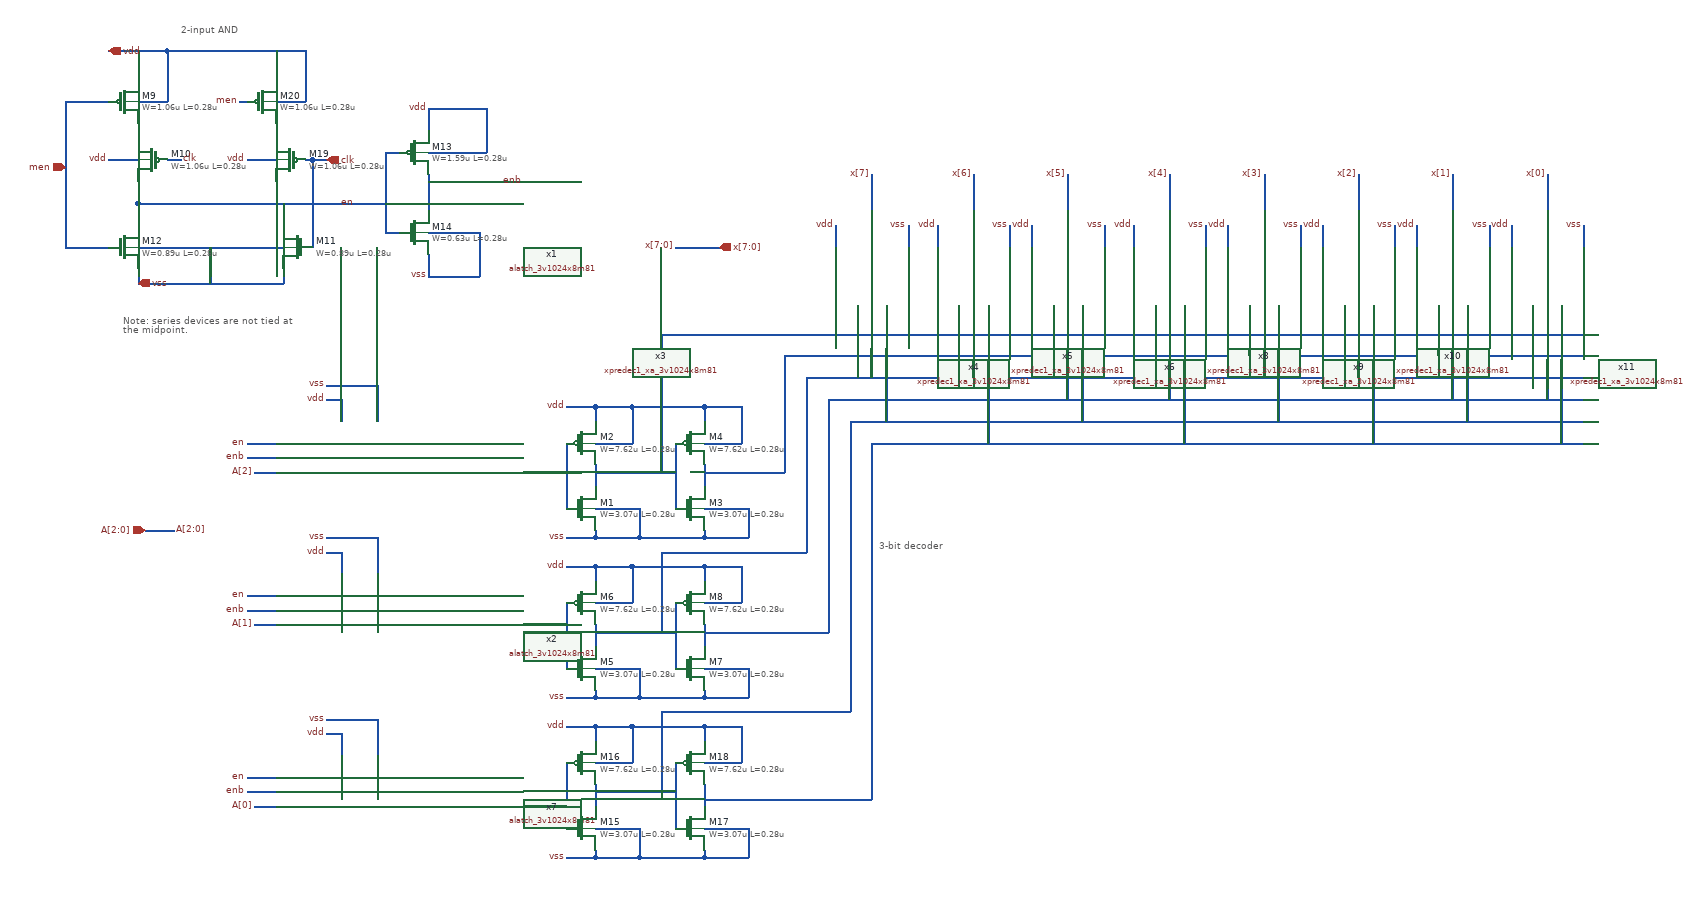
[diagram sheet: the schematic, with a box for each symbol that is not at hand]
v {xschem version=3.4.6 file_version=1.2}
G {}
K {}
V {}
S {}
E {}
T {2-input AND} -90 -410 0 0 0.4 0.4 {}
T {3-bit decoder} 870 300 0 0 0.4 0.4 {}
T {Note: series devices are not tied at
the midpoint.} -170 -10 0 0 0.3 0.3 {}
N 10 210 40 210 {lab=A[2]}
N 10 420 40 420 {lab=A[1]}
N -140 290 -100 290 {lab=A[2:0]}
N 860 -200 860 -150 {lab=x[7]}
N 1000 -200 1000 -150 {lab=x[6]}
N 1130 -200 1130 -150 {lab=x[5]}
N 1270 -200 1270 -150 {lab=x[4]}
N 440 170 440 260 {lab=#net1}
N 480 120 480 140 {lab=vdd}
N 480 120 530 120 {lab=vdd}
N 530 120 530 170 {lab=vdd}
N 480 170 530 170 {lab=vdd}
N 480 260 540 260 {lab=vss}
N 540 260 540 300 {lab=vss}
N 480 300 540 300 {lab=vss}
N 480 290 480 300 {lab=vss}
N 480 200 480 230 {lab=#net2}
N 480 210 590 210 {lab=#net2}
N 590 170 590 260 {lab=#net2}
N 630 120 630 140 {lab=vdd}
N 630 120 680 120 {lab=vdd}
N 680 120 680 170 {lab=vdd}
N 630 170 680 170 {lab=vdd}
N 630 260 690 260 {lab=vss}
N 690 260 690 300 {lab=vss}
N 630 300 690 300 {lab=vss}
N 630 290 630 300 {lab=vss}
N 630 200 630 230 {lab=#net3}
N 630 210 740 210 {lab=#net3}
N 250 210 440 210 {lab=#net1}
N 530 120 630 120 {lab=vdd}
N 540 300 630 300 {lab=vss}
N 440 300 480 300 {lab=vss}
N 440 120 480 120 {lab=vdd}
N 440 390 440 480 {lab=#net4}
N 480 340 480 360 {lab=vdd}
N 480 340 530 340 {lab=vdd}
N 530 340 530 390 {lab=vdd}
N 480 390 530 390 {lab=vdd}
N 480 480 540 480 {lab=vss}
N 540 480 540 520 {lab=vss}
N 480 520 540 520 {lab=vss}
N 480 510 480 520 {lab=vss}
N 480 420 480 450 {lab=#net5}
N 480 430 590 430 {lab=#net5}
N 590 390 590 480 {lab=#net5}
N 630 340 630 360 {lab=vdd}
N 630 340 680 340 {lab=vdd}
N 680 340 680 390 {lab=vdd}
N 630 390 680 390 {lab=vdd}
N 630 480 690 480 {lab=vss}
N 690 480 690 520 {lab=vss}
N 630 520 690 520 {lab=vss}
N 630 510 630 520 {lab=vss}
N 630 420 630 450 {lab=#net6}
N 630 430 740 430 {lab=#net6}
N 530 340 630 340 {lab=vdd}
N 540 520 630 520 {lab=vss}
N 440 520 480 520 {lab=vss}
N 440 340 480 340 {lab=vdd}
N 250 420 440 420 {lab=#net4}
N 0 170 40 170 {lab=en}
N 0 380 40 380 {lab=en}
N -0 190 40 190 {lab=enb}
N 0 400 40 400 {lab=enb}
N 250 -200 250 -150 {lab=enb}
N 190 -230 210 -230 {lab=en}
N 190 -230 190 -120 {lab=en}
N 190 -120 210 -120 {lab=en}
N 250 -190 350 -190 {lab=enb}
N 250 -90 250 -60 {lab=vss}
N 250 -60 320 -60 {lab=vss}
N 320 -120 320 -60 {lab=vss}
N 250 -120 320 -120 {lab=vss}
N 250 -290 250 -260 {lab=vdd}
N 250 -290 330 -290 {lab=vdd}
N 330 -290 330 -230 {lab=vdd}
N 250 -230 330 -230 {lab=vdd}
N 130 110 130 140 {lab=vdd}
N 110 110 130 110 {lab=vdd}
N 180 90 180 140 {lab=vss}
N 110 90 180 90 {lab=vss}
N 130 320 130 350 {lab=vdd}
N 110 320 130 320 {lab=vdd}
N 180 300 180 350 {lab=vss}
N 110 300 180 300 {lab=vss}
N 810 -130 810 -100 {lab=vdd}
N 910 -130 910 -100 {lab=vss}
N 950 -130 950 -100 {lab=vdd}
N 1050 -130 1050 -100 {lab=vss}
N 1080 -130 1080 -100 {lab=vdd}
N 1180 -130 1180 -100 {lab=vss}
N 1220 -130 1220 -100 {lab=vdd}
N 1320 -130 1320 -100 {lab=vss}
N -150 -270 -150 -250 {lab=#net7}
N -150 -370 -150 -330 {lab=vdd}
N -150 -300 -110 -300 {lab=vdd}
N -110 -370 -110 -300 {lab=vdd}
N -190 -370 -110 -370 {lab=vdd}
N -250 -300 -250 -100 {lab=men}
N -150 -70 -150 -50 {lab=vss}
N -150 -50 50 -50 {lab=vss}
N 50 -70 50 -50 {lab=vss}
N -150 -100 50 -100 {lab=vss}
N -50 -100 -50 -50 {lab=vss}
N 90 -220 90 -100 {lab=clk}
N -150 -160 -150 -130 {lab=en}
N -150 -160 190 -160 {lab=en}
N 50 -160 50 -130 {lab=en}
N -150 -190 -150 -160 {lab=en}
N 570 20 570 210 {lab=#net2}
N 740 50 740 210 {lab=#net3}
N 570 320 570 430 {lab=#net5}
N 570 320 770 320 {lab=#net5}
N 770 80 770 320 {lab=#net5}
N 740 430 800 430 {lab=#net6}
N 800 120 800 430 {lab=#net6}
N 800 110 800 120 {lab=#net6}
N 590 -100 650 -100 {lab=x[7:0]}
N 10 670 40 670 {lab=A[0]}
N 0 630 40 630 {lab=en}
N 0 650 40 650 {lab=enb}
N 130 570 130 600 {lab=vdd}
N 110 570 130 570 {lab=vdd}
N 180 550 180 600 {lab=vss}
N 110 550 180 550 {lab=vss}
N 440 610 440 700 {lab=#net8}
N 480 560 480 580 {lab=vdd}
N 480 560 530 560 {lab=vdd}
N 530 560 530 610 {lab=vdd}
N 480 610 530 610 {lab=vdd}
N 480 700 540 700 {lab=vss}
N 540 700 540 740 {lab=vss}
N 480 740 540 740 {lab=vss}
N 480 730 480 740 {lab=vss}
N 480 640 480 670 {lab=#net9}
N 480 650 590 650 {lab=#net9}
N 590 610 590 700 {lab=#net9}
N 630 560 630 580 {lab=vdd}
N 630 560 680 560 {lab=vdd}
N 680 560 680 610 {lab=vdd}
N 630 610 680 610 {lab=vdd}
N 630 700 690 700 {lab=vss}
N 690 700 690 740 {lab=vss}
N 630 740 690 740 {lab=vss}
N 630 730 630 740 {lab=vss}
N 630 640 630 670 {lab=#net10}
N 530 560 630 560 {lab=vdd}
N 540 740 630 740 {lab=vss}
N 440 740 480 740 {lab=vss}
N 440 560 480 560 {lab=vdd}
N 250 670 440 670 {lab=#net8}
N 570 540 570 650 {lab=#net9}
N 830 140 830 540 {lab=#net9}
N 570 540 830 540 {lab=#net9}
N 860 170 860 660 {lab=#net10}
N 630 660 860 660 {lab=#net10}
N 1400 -200 1400 -150 {lab=x[3]}
N 1350 -130 1350 -100 {lab=vdd}
N 1450 -130 1450 -100 {lab=vss}
N 1530 -200 1530 -150 {lab=x[2]}
N 1480 -130 1480 -100 {lab=vdd}
N 1580 -130 1580 -100 {lab=vss}
N 1660 -200 1660 -150 {lab=x[1]}
N 1610 -130 1610 -100 {lab=vdd}
N 1710 -130 1710 -100 {lab=vss}
N 1790 -200 1790 -150 {lab=x[0]}
N 1740 -130 1740 -100 {lab=vdd}
N 1840 -130 1840 -100 {lab=vss}
N 860 170 1840 170 {lab=#net10}
N 830 140 1840 140 {lab=#net9}
N 800 110 1840 110 {lab=#net6}
N 770 80 1840 80 {lab=#net5}
N 740 50 1840 50 {lab=#net3}
N 570 20 1840 20 {lab=#net2}
N 840 -20 840 20 {lab=#net2}
N 860 -20 860 80 {lab=#net5}
N 880 -20 880 140 {lab=#net9}
N 980 -20 980 20 {lab=#net2}
N 1000 -20 1000 80 {lab=#net5}
N 1020 -20 1020 170 {lab=#net10}
N 1110 -20 1110 20 {lab=#net2}
N 1130 -20 1130 110 {lab=#net6}
N 1150 -20 1150 140 {lab=#net9}
N 1250 -20 1250 20 {lab=#net2}
N 1270 -20 1270 110 {lab=#net6}
N 1290 -20 1290 170 {lab=#net10}
N 1380 -20 1380 50 {lab=#net3}
N 1510 -20 1510 50 {lab=#net3}
N 1640 -20 1640 50 {lab=#net3}
N 1770 -20 1770 50 {lab=#net3}
N 1400 -20 1400 80 {lab=#net5}
N 1420 -20 1420 140 {lab=#net9}
N 1530 -20 1530 80 {lab=#net5}
N 1550 -20 1550 170 {lab=#net10}
N 1660 -20 1660 110 {lab=#net6}
N 1680 -20 1680 140 {lab=#net9}
N 1790 -20 1790 110 {lab=#net6}
N 1810 -20 1810 170 {lab=#net10}
N -190 -220 -150 -220 {lab=vdd}
N 40 -270 40 -250 {lab=#net11}
N 40 -300 80 -300 {lab=vdd}
N 0 -220 40 -220 {lab=vdd}
N -250 -300 -190 -300 {lab=men}
N 80 -220 90 -220 {lab=clk}
N -250 -100 -190 -100 {lab=men}
N -110 -370 80 -370 {lab=vdd}
N 80 -370 80 -300 {lab=vdd}
N 40 -370 40 -330 {lab=vdd}
N -10 -300 -0 -300 {lab=men}
N -110 -220 -90 -220 {lab=clk}
N 40 -190 40 -160 {lab=en}
N 90 -220 110 -220 {lab=clk}
C {alatch_3v1024x8m81.sym} 190 190 0 0 {name=x1}
C {alatch_3v1024x8m81.sym} 190 400 0 0 {name=x2}
C {lab_pin.sym} 10 210 0 0 {name=p1 sig_type=std_logic lab=A[2]}
C {lab_pin.sym} 10 420 0 0 {name=p2 sig_type=std_logic lab=A[1]}
C {ipin.sym} -140 290 0 0 {name=p3 lab=A[2:0]}
C {lab_pin.sym} -100 290 0 1 {name=p4 sig_type=std_logic lab=A[2:0]}
C {lab_pin.sym} 860 -200 1 0 {name=p5 sig_type=std_logic lab=x[7]}
C {lab_pin.sym} 1000 -200 1 0 {name=p6 sig_type=std_logic lab=x[6]}
C {lab_pin.sym} 1130 -200 1 0 {name=p7 sig_type=std_logic lab=x[5]}
C {lab_pin.sym} 1270 -200 1 0 {name=p8 sig_type=std_logic lab=x[4]}
C {symbols/nfet_03v3.sym} 460 260 0 0 {name=M1
L=0.28u
W=3.07u
nf=1
m=1
ad="'int((nf+1)/2) * W/nf * 0.18u'"
pd="'2*int((nf+1)/2) * (W/nf + 0.18u)'"
as="'int((nf+2)/2) * W/nf * 0.18u'"
ps="'2*int((nf+2)/2) * (W/nf + 0.18u)'"
nrd="'0.18u / W'" nrs="'0.18u / W'"
sa=0 sb=0 sd=0
model=nfet_03v3
spiceprefix=X
}
C {symbols/pfet_03v3.sym} 460 170 0 0 {name=M2
L=0.28u
W=7.62u
nf=1
m=1
ad="'int((nf+1)/2) * W/nf * 0.18u'"
pd="'2*int((nf+1)/2) * (W/nf + 0.18u)'"
as="'int((nf+2)/2) * W/nf * 0.18u'"
ps="'2*int((nf+2)/2) * (W/nf + 0.18u)'"
nrd="'0.18u / W'" nrs="'0.18u / W'"
sa=0 sb=0 sd=0
model=pfet_03v3
spiceprefix=X
}
C {symbols/nfet_03v3.sym} 610 260 0 0 {name=M3
L=0.28u
W=3.07u
nf=1
m=1
ad="'int((nf+1)/2) * W/nf * 0.18u'"
pd="'2*int((nf+1)/2) * (W/nf + 0.18u)'"
as="'int((nf+2)/2) * W/nf * 0.18u'"
ps="'2*int((nf+2)/2) * (W/nf + 0.18u)'"
nrd="'0.18u / W'" nrs="'0.18u / W'"
sa=0 sb=0 sd=0
model=nfet_03v3
spiceprefix=X
}
C {symbols/pfet_03v3.sym} 610 170 0 0 {name=M4
L=0.28u
W=7.62u
nf=1
m=1
ad="'int((nf+1)/2) * W/nf * 0.18u'"
pd="'2*int((nf+1)/2) * (W/nf + 0.18u)'"
as="'int((nf+2)/2) * W/nf * 0.18u'"
ps="'2*int((nf+2)/2) * (W/nf + 0.18u)'"
nrd="'0.18u / W'" nrs="'0.18u / W'"
sa=0 sb=0 sd=0
model=pfet_03v3
spiceprefix=X
}
C {lab_pin.sym} 440 120 0 0 {name=p9 sig_type=std_logic lab=vdd}
C {lab_pin.sym} 440 300 0 0 {name=p10 sig_type=std_logic lab=vss}
C {symbols/nfet_03v3.sym} 460 480 0 0 {name=M5
L=0.28u
W=3.07u
nf=1
m=1
ad="'int((nf+1)/2) * W/nf * 0.18u'"
pd="'2*int((nf+1)/2) * (W/nf + 0.18u)'"
as="'int((nf+2)/2) * W/nf * 0.18u'"
ps="'2*int((nf+2)/2) * (W/nf + 0.18u)'"
nrd="'0.18u / W'" nrs="'0.18u / W'"
sa=0 sb=0 sd=0
model=nfet_03v3
spiceprefix=X
}
C {symbols/pfet_03v3.sym} 460 390 0 0 {name=M6
L=0.28u
W=7.62u
nf=1
m=1
ad="'int((nf+1)/2) * W/nf * 0.18u'"
pd="'2*int((nf+1)/2) * (W/nf + 0.18u)'"
as="'int((nf+2)/2) * W/nf * 0.18u'"
ps="'2*int((nf+2)/2) * (W/nf + 0.18u)'"
nrd="'0.18u / W'" nrs="'0.18u / W'"
sa=0 sb=0 sd=0
model=pfet_03v3
spiceprefix=X
}
C {symbols/nfet_03v3.sym} 610 480 0 0 {name=M7
L=0.28u
W=3.07u
nf=1
m=1
ad="'int((nf+1)/2) * W/nf * 0.18u'"
pd="'2*int((nf+1)/2) * (W/nf + 0.18u)'"
as="'int((nf+2)/2) * W/nf * 0.18u'"
ps="'2*int((nf+2)/2) * (W/nf + 0.18u)'"
nrd="'0.18u / W'" nrs="'0.18u / W'"
sa=0 sb=0 sd=0
model=nfet_03v3
spiceprefix=X
}
C {symbols/pfet_03v3.sym} 610 390 0 0 {name=M8
L=0.28u
W=7.62u
nf=1
m=1
ad="'int((nf+1)/2) * W/nf * 0.18u'"
pd="'2*int((nf+1)/2) * (W/nf + 0.18u)'"
as="'int((nf+2)/2) * W/nf * 0.18u'"
ps="'2*int((nf+2)/2) * (W/nf + 0.18u)'"
nrd="'0.18u / W'" nrs="'0.18u / W'"
sa=0 sb=0 sd=0
model=pfet_03v3
spiceprefix=X
}
C {lab_pin.sym} 440 340 0 0 {name=p11 sig_type=std_logic lab=vdd}
C {lab_pin.sym} 440 520 0 0 {name=p12 sig_type=std_logic lab=vss}
C {symbols/pfet_03v3.sym} -170 -300 0 0 {name=M9
L=0.28u
W=1.06u
nf=1
m=1
ad="'int((nf+1)/2) * W/nf * 0.18u'"
pd="'2*int((nf+1)/2) * (W/nf + 0.18u)'"
as="'int((nf+2)/2) * W/nf * 0.18u'"
ps="'2*int((nf+2)/2) * (W/nf + 0.18u)'"
nrd="'0.18u / W'" nrs="'0.18u / W'"
sa=0 sb=0 sd=0
model=pfet_03v3
spiceprefix=X
}
C {symbols/pfet_03v3.sym} -130 -220 0 1 {name=M10
L=0.28u
W=1.06u
nf=1
m=1
ad="'int((nf+1)/2) * W/nf * 0.18u'"
pd="'2*int((nf+1)/2) * (W/nf + 0.18u)'"
as="'int((nf+2)/2) * W/nf * 0.18u'"
ps="'2*int((nf+2)/2) * (W/nf + 0.18u)'"
nrd="'0.18u / W'" nrs="'0.18u / W'"
sa=0 sb=0 sd=0
model=pfet_03v3
spiceprefix=X
}
C {symbols/nfet_03v3.sym} 70 -100 0 1 {name=M11
L=0.28u
W=0.89u
nf=1
m=1
ad="'int((nf+1)/2) * W/nf * 0.18u'"
pd="'2*int((nf+1)/2) * (W/nf + 0.18u)'"
as="'int((nf+2)/2) * W/nf * 0.18u'"
ps="'2*int((nf+2)/2) * (W/nf + 0.18u)'"
nrd="'0.18u / W'" nrs="'0.18u / W'"
sa=0 sb=0 sd=0
model=nfet_03v3
spiceprefix=X
}
C {symbols/nfet_03v3.sym} -170 -100 0 0 {name=M12
L=0.28u
W=0.89u
nf=1
m=1
ad="'int((nf+1)/2) * W/nf * 0.18u'"
pd="'2*int((nf+1)/2) * (W/nf + 0.18u)'"
as="'int((nf+2)/2) * W/nf * 0.18u'"
ps="'2*int((nf+2)/2) * (W/nf + 0.18u)'"
nrd="'0.18u / W'" nrs="'0.18u / W'"
sa=0 sb=0 sd=0
model=nfet_03v3
spiceprefix=X
}
C {ipin.sym} 110 -220 0 1 {name=p16 lab=clk}
C {ipin.sym} -250 -210 0 0 {name=p17 lab=men}
C {lab_pin.sym} 0 170 0 0 {name=p19 sig_type=std_logic lab=en}
C {lab_pin.sym} 0 380 0 0 {name=p20 sig_type=std_logic lab=en}
C {lab_pin.sym} 0 190 0 0 {name=p21 sig_type=std_logic lab=enb}
C {lab_pin.sym} 0 400 0 0 {name=p22 sig_type=std_logic lab=enb}
C {lab_wire.sym} 150 -160 0 0 {name=p18 sig_type=std_logic lab=en}
C {symbols/pfet_03v3.sym} 230 -230 0 0 {name=M13
L=0.28u
W=1.59u
nf=2
m=1
ad="'int((nf+1)/2) * W/nf * 0.18u'"
pd="'2*int((nf+1)/2) * (W/nf + 0.18u)'"
as="'int((nf+2)/2) * W/nf * 0.18u'"
ps="'2*int((nf+2)/2) * (W/nf + 0.18u)'"
nrd="'0.18u / W'" nrs="'0.18u / W'"
sa=0 sb=0 sd=0
model=pfet_03v3
spiceprefix=X
}
C {symbols/nfet_03v3.sym} 230 -120 0 0 {name=M14
L=0.28u
W=0.63u
nf=1
m=1
ad="'int((nf+1)/2) * W/nf * 0.18u'"
pd="'2*int((nf+1)/2) * (W/nf + 0.18u)'"
as="'int((nf+2)/2) * W/nf * 0.18u'"
ps="'2*int((nf+2)/2) * (W/nf + 0.18u)'"
nrd="'0.18u / W'" nrs="'0.18u / W'"
sa=0 sb=0 sd=0
model=nfet_03v3
spiceprefix=X
}
C {lab_pin.sym} 350 -190 0 1 {name=p23 sig_type=std_logic lab=enb}
C {lab_pin.sym} 250 -290 0 0 {name=p24 sig_type=std_logic lab=vdd}
C {lab_pin.sym} 250 -60 0 0 {name=p25 sig_type=std_logic lab=vss}
C {lab_pin.sym} 110 90 0 0 {name=p26 sig_type=std_logic lab=vss}
C {lab_pin.sym} 110 300 0 0 {name=p27 sig_type=std_logic lab=vss}
C {lab_pin.sym} 110 110 0 0 {name=p28 sig_type=std_logic lab=vdd}
C {lab_pin.sym} 110 320 0 0 {name=p29 sig_type=std_logic lab=vdd}
C {lab_pin.sym} 810 -130 1 0 {name=p30 sig_type=std_logic lab=vdd}
C {lab_pin.sym} 950 -130 1 0 {name=p31 sig_type=std_logic lab=vdd}
C {lab_pin.sym} 1080 -130 1 0 {name=p32 sig_type=std_logic lab=vdd}
C {lab_pin.sym} 1220 -130 1 0 {name=p33 sig_type=std_logic lab=vdd}
C {lab_pin.sym} 910 -130 1 0 {name=p34 sig_type=std_logic lab=vss}
C {lab_pin.sym} 1050 -130 1 0 {name=p35 sig_type=std_logic lab=vss}
C {lab_pin.sym} 1180 -130 1 0 {name=p36 sig_type=std_logic lab=vss}
C {lab_pin.sym} 1320 -130 1 0 {name=p37 sig_type=std_logic lab=vss}
C {opin.sym} 650 -100 0 0 {name=p15 lab=x[7:0]}
C {lab_pin.sym} 590 -100 0 0 {name=p38 sig_type=std_logic lab=x[7:0]}
C {iopin.sym} -190 -370 0 1 {name=p39 lab=vdd}
C {iopin.sym} -150 -50 0 1 {name=p40 lab=vss}
C {alatch_3v1024x8m81.sym} 190 650 0 0 {name=x7}
C {lab_pin.sym} 10 670 0 0 {name=p13 sig_type=std_logic lab=A[0]}
C {lab_pin.sym} 0 630 0 0 {name=p14 sig_type=std_logic lab=en}
C {lab_pin.sym} 0 650 0 0 {name=p41 sig_type=std_logic lab=enb}
C {lab_pin.sym} 110 550 0 0 {name=p42 sig_type=std_logic lab=vss}
C {lab_pin.sym} 110 570 0 0 {name=p43 sig_type=std_logic lab=vdd}
C {symbols/nfet_03v3.sym} 460 700 0 0 {name=M15
L=0.28u
W=3.07u
nf=1
m=1
ad="'int((nf+1)/2) * W/nf * 0.18u'"
pd="'2*int((nf+1)/2) * (W/nf + 0.18u)'"
as="'int((nf+2)/2) * W/nf * 0.18u'"
ps="'2*int((nf+2)/2) * (W/nf + 0.18u)'"
nrd="'0.18u / W'" nrs="'0.18u / W'"
sa=0 sb=0 sd=0
model=nfet_03v3
spiceprefix=X
}
C {symbols/pfet_03v3.sym} 460 610 0 0 {name=M16
L=0.28u
W=7.62u
nf=1
m=1
ad="'int((nf+1)/2) * W/nf * 0.18u'"
pd="'2*int((nf+1)/2) * (W/nf + 0.18u)'"
as="'int((nf+2)/2) * W/nf * 0.18u'"
ps="'2*int((nf+2)/2) * (W/nf + 0.18u)'"
nrd="'0.18u / W'" nrs="'0.18u / W'"
sa=0 sb=0 sd=0
model=pfet_03v3
spiceprefix=X
}
C {symbols/nfet_03v3.sym} 610 700 0 0 {name=M17
L=0.28u
W=3.07u
nf=1
m=1
ad="'int((nf+1)/2) * W/nf * 0.18u'"
pd="'2*int((nf+1)/2) * (W/nf + 0.18u)'"
as="'int((nf+2)/2) * W/nf * 0.18u'"
ps="'2*int((nf+2)/2) * (W/nf + 0.18u)'"
nrd="'0.18u / W'" nrs="'0.18u / W'"
sa=0 sb=0 sd=0
model=nfet_03v3
spiceprefix=X
}
C {symbols/pfet_03v3.sym} 610 610 0 0 {name=M18
L=0.28u
W=7.62u
nf=1
m=1
ad="'int((nf+1)/2) * W/nf * 0.18u'"
pd="'2*int((nf+1)/2) * (W/nf + 0.18u)'"
as="'int((nf+2)/2) * W/nf * 0.18u'"
ps="'2*int((nf+2)/2) * (W/nf + 0.18u)'"
nrd="'0.18u / W'" nrs="'0.18u / W'"
sa=0 sb=0 sd=0
model=pfet_03v3
spiceprefix=X
}
C {lab_pin.sym} 440 560 0 0 {name=p44 sig_type=std_logic lab=vdd}
C {lab_pin.sym} 440 740 0 0 {name=p45 sig_type=std_logic lab=vss}
C {xpredec1_xa_3v1024x8m81.sym} 860 -130 3 0 {name=x3}
C {xpredec1_xa_3v1024x8m81.sym} 1000 -130 3 0 {name=x4}
C {xpredec1_xa_3v1024x8m81.sym} 1130 -130 3 0 {name=x5}
C {xpredec1_xa_3v1024x8m81.sym} 1270 -130 3 0 {name=x6}
C {xpredec1_xa_3v1024x8m81.sym} 1400 -130 3 0 {name=x8}
C {xpredec1_xa_3v1024x8m81.sym} 1530 -130 3 0 {name=x9}
C {xpredec1_xa_3v1024x8m81.sym} 1660 -130 3 0 {name=x10}
C {xpredec1_xa_3v1024x8m81.sym} 1790 -130 3 0 {name=x11}
C {lab_pin.sym} 1400 -200 1 0 {name=p46 sig_type=std_logic lab=x[3]}
C {lab_pin.sym} 1350 -130 1 0 {name=p47 sig_type=std_logic lab=vdd}
C {lab_pin.sym} 1450 -130 1 0 {name=p48 sig_type=std_logic lab=vss}
C {lab_pin.sym} 1530 -200 1 0 {name=p49 sig_type=std_logic lab=x[2]}
C {lab_pin.sym} 1480 -130 1 0 {name=p50 sig_type=std_logic lab=vdd}
C {lab_pin.sym} 1580 -130 1 0 {name=p51 sig_type=std_logic lab=vss}
C {lab_pin.sym} 1660 -200 1 0 {name=p52 sig_type=std_logic lab=x[1]}
C {lab_pin.sym} 1610 -130 1 0 {name=p53 sig_type=std_logic lab=vdd}
C {lab_pin.sym} 1710 -130 1 0 {name=p54 sig_type=std_logic lab=vss}
C {lab_pin.sym} 1790 -200 1 0 {name=p55 sig_type=std_logic lab=x[0]}
C {lab_pin.sym} 1740 -130 1 0 {name=p56 sig_type=std_logic lab=vdd}
C {lab_pin.sym} 1840 -130 1 0 {name=p57 sig_type=std_logic lab=vss}
C {lab_pin.sym} -190 -220 0 0 {name=p58 sig_type=std_logic lab=vdd}
C {lab_pin.sym} 0 -220 0 0 {name=p59 sig_type=std_logic lab=vdd}
C {lab_pin.sym} -10 -300 0 0 {name=p60 sig_type=std_logic lab=men}
C {lab_pin.sym} -90 -220 0 1 {name=p61 sig_type=std_logic lab=clk}
C {symbols/pfet_03v3.sym} 60 -220 0 1 {name=M19
L=0.28u
W=1.06u
nf=1
m=1
ad="'int((nf+1)/2) * W/nf * 0.18u'"
pd="'2*int((nf+1)/2) * (W/nf + 0.18u)'"
as="'int((nf+2)/2) * W/nf * 0.18u'"
ps="'2*int((nf+2)/2) * (W/nf + 0.18u)'"
nrd="'0.18u / W'" nrs="'0.18u / W'"
sa=0 sb=0 sd=0
model=pfet_03v3
spiceprefix=X
}
C {symbols/pfet_03v3.sym} 20 -300 0 0 {name=M20
L=0.28u
W=1.06u
nf=1
m=1
ad="'int((nf+1)/2) * W/nf * 0.18u'"
pd="'2*int((nf+1)/2) * (W/nf + 0.18u)'"
as="'int((nf+2)/2) * W/nf * 0.18u'"
ps="'2*int((nf+2)/2) * (W/nf + 0.18u)'"
nrd="'0.18u / W'" nrs="'0.18u / W'"
sa=0 sb=0 sd=0
model=pfet_03v3
spiceprefix=X
}
